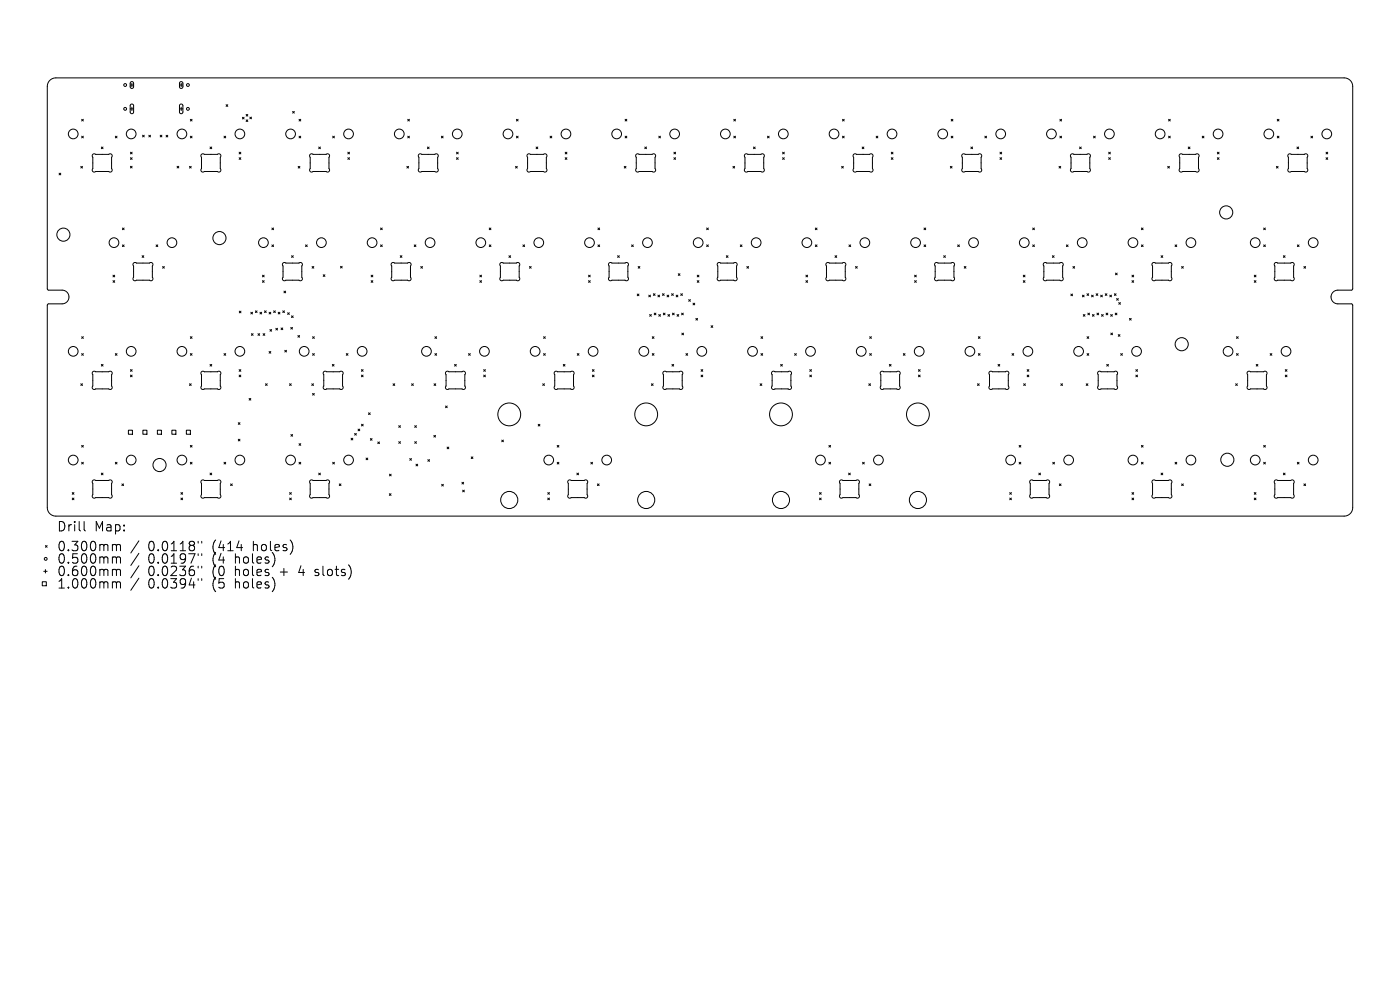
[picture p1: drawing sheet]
<svg xmlns="http://www.w3.org/2000/svg" width="297mm" height="210mm" viewBox="0 0 297 210" stroke-linecap="round" stroke-linejoin="round" font-family="sans-serif">
<defs><g id="words">
<g font-size="2.8">
<text x="12" y="113">Drill</text>
<text x="20" y="113">Map:</text>
<text x="12" y="117.2">0.300mm</text>
<text x="12" y="119.9">0.500mm</text>
<text x="31.4" y="117.2">0.0118&quot;</text>
<text x="31.4" y="119.9">0.0197&quot;</text>
<text x="45.2" y="117.2">(414</text>
<text x="45.2" y="119.9">(4</text>
<text x="50.1" y="119.9">holes)</text>
<text x="53.9" y="117.2">holes)</text>
<text x="12" y="122.5">0.600mm</text>
<text x="12" y="125.1">1.000mm</text>
<text x="31.4" y="122.5">0.0236&quot;</text>
<text x="31.4" y="125.1">0.0394&quot;</text>
<text x="45.2" y="122.5">(0</text>
<text x="45.2" y="125.1">(5</text>
<text x="50.1" y="122.5">holes</text>
<text x="50.1" y="125.1">holes)</text>
<text x="59.9" y="122.5">+</text>
<text x="64.1" y="122.5">4</text>
<text x="67.7" y="122.5">slots)</text>
</g>
</g></defs>
<g fill="none" stroke="#000" stroke-width=".21">
<path d="M10.6 17.1l.6-.5 .6-.1h273.4a1.81 1.81 0 0 1 1.8 1.8v43l-.3 .2h-2.9a1.45 1.45 0 0 0-1.4 1.5 1.45 1.45 0 0 0 1.4 1.5h2.9l.3 .2v43a1.81 1.81 0 0 1-1.8 1.8h-273.4a1.82 1.82 0 0 1-1.8-1.8v-43l.3-.2h2.9a1.45 1.45 0 0 0 1.4-1.5 1.45 1.45 0 0 0-1.4-1.5h-2.9l-.3-.2v-43l.2-.7zM27.6 18h.7M27.7 17.4l.4-.1 .2 .3v.9l-.2 .2h-.3l-.2-.2zM28 17.7v.7M38.1 18h.7M38.2 17.4l.3-.1 .3 .3v.9l-.3 .2h-.2l-.2-.2zM38.4 17.7v.7M12.5 36.7l.4 .4M12.9 36.7l-.4 .4M17.1 35.3l.4 .4M17.3 25.3l.4 .4M17.3 28.9l.4 .4"/>
<path d="M17.5 35.3l-.4 .4M17.7 25.3l-.4 .4M17.7 28.9l-.4 .4M19.7 32.7l.3-.1 .3 .1h2.8l.3-.1 .3 .1 .1 .4-.1 .3v3l-.3 .1-.3-.1h-2.8l-.3 .1-.3-.1-.1-.3 .1-.3v-2.4l-.1-.3zM21.5 31.2l.4 .3M21.9 31.2l-.4 .3M24.5 28.9l.3 .4M24.8 28.9l-.3 .4M27.6 23.1h.7M27.7 35.3l.3 .3M27.7 32.3l.3 .4M27.7 33.5l.3 .3"/>
<path d="M27.7 22.2l.4-.1 .2 .3v1.4l-.3 .3h-.2l-.2-.3zM28 22.7v.8M28 35.3l-.3 .3M28 32.3l-.3 .4M28 33.5l-.3 .3M30.2 28.7l.4 .3M30.6 28.7l-.4 .3M31.6 28.7l.3 .4M31.9 28.7l-.3 .4M34 28.7l.3 .3M34.3 28.7l-.3 .3M35.2 28.7l.4 .4"/>
<path d="M35.6 28.7l-.4 .4M37.6 35.3l.3 .3M37.9 35.3l-.3 .3M38.1 23.1h.7M38.2 22.2l.3-.1 .3 .3v1.4l-.3 .3h-.3l-.1-.3zM38.4 22.7v.8M40.2 35.3l.4 .4M40.4 25.3l.3 .4M40.4 28.9l.3 .4M40.6 35.3l-.4 .4M40.7 25.3l-.3 .4M40.7 28.9l-.3 .4"/>
<path d="M42.7 32.7l.3-.1 .3 .1h2.8l.3-.1 .3 .1 .2 .4-.2 .3 .1 3-.4 .1-.3-.1h-2.8l-.3 .1-.2-.1-.2-.3 .1-.3v-2.4l-.1-.3zM44.6 31.2l.3 .3M44.9 31.2l-.3 .3M47.5 28.9l.4 .4M47.9 28.9l-.4 .4M48 22.2l.3 .4M48.3 22.2l-.3 .4M50.7 32.3l.4 .4M50.7 33.5l.4 .3M51.1 32.3l-.4 .4M51.1 33.5l-.4 .3M51.4 24.9l.4 .3"/>
<path d="M51.8 24.9l-.4 .3M52.2 24.3l.4 .3M52.2 25.4l.4 .4M52.6 24.3l-.4 .3M52.6 25.4l-.4 .4M53 24.8l.4 .4M53.4 24.8l-.4 .4M62.1 23.6l.3 .4M62.4 23.6l-.3 .4M63.3 35.3l.3 .4M63.4 25.3l.4 .4M63.4 28.9l.4 .4"/>
<path d="M63.6 35.3l-.3 .4M63.8 25.3l-.4 .4M63.8 28.9l-.4 .4M65.8 32.7l.3-.1 .3 .1h2.8l.3-.1 .3 .1 .1 .4-.1 .3v3l-.3 .1-.3-.1h-2.8l-.3 .1-.3-.1-.1-.3 .1-.3v-2.4l-.1-.3zM67.6 31.2l.4 .3M68 31.2l-.4 .3M70.6 28.9l.3 .4M70.9 28.9l-.3 .4M73.8 32.3l.4 .4M73.8 33.5l.4 .3M74.2 32.3l-.4 .4M74.2 33.5l-.4 .3"/>
<path d="M86.3 35.3l.4 .4M86.5 25.3l.4 .4M86.5 28.9l.4 .4M86.7 35.3l-.4 .4M86.9 28.9l-.4 .4M86.9 25.3l-.4 .4M88.9 32.7l.3-.1 .3 .1h2.7l.4-.1 .2 .1 .2 .4-.2 .3 .1 3-.4 .1-.3-.1h-2.7l-.3 .1-.3-.1-.2-.3 .2-.3v-2.4l-.2-.3zM90.7 31.2l.3 .3M91 31.2l-.3 .3M93.6 28.9l.4 .4M94 28.9l-.4 .4M96.8 32.3l.4 .4"/>
<path d="M96.8 33.5l.4 .3M97.2 33.5l-.4 .3M97.2 32.3l-.4 .4M109.4 35.3l.3 .4M109.6 25.3l.3 .4M109.6 28.9l.3 .4M109.7 35.3l-.3 .4M109.9 25.3l-.3 .4M109.9 28.9l-.3 .4M111.9 32.7l.3-.1 .3 .1h2.8l.3-.1 .3 .1 .1 .4-.1 .3v3l-.3 .1-.3-.1h-2.8l-.3 .1-.3-.1-.1-.3 .1-.3v-2.4l-.1-.3zM113.7 31.2l.4 .3M114.1 31.2l-.4 .3"/>
<path d="M116.7 28.9l.4 .4M117.1 28.9l-.4 .4M119.9 32.3l.4 .4M119.9 33.5l.4 .3M120.3 32.3l-.4 .4M120.3 33.5l-.4 .3M132.4 35.3l.4 .4M132.6 25.3l.4 .4M132.6 28.9l.4 .4M132.8 35.3l-.4 .4M133 28.9l-.4 .4M133 25.3l-.4 .4"/>
<path d="M135 32.7l.3-.1 .3 .1h2.8l.3-.1 .2 .1 .2 .4-.1 .3v3l-.3 .1-.3-.1h-2.8l-.3 .1-.3-.1-.2-.3 .2-.3v-2.4l-.2-.3zM136.8 31.2l.4 .3M137.2 31.2l-.4 .3M139.8 28.9l.3 .4M140.1 28.9l-.3 .4M143 32.3l.3 .4M143 33.5l.3 .3M143.3 32.3l-.3 .4M143.3 33.5l-.3 .3M155.5 35.3l.4 .4M155.7 25.3l.3 .4M155.7 28.9l.3 .4"/>
<path d="M155.9 35.3l-.4 .4M156 25.3l-.3 .4M156 28.9l-.3 .4M158 32.7l.3-.1 .3 .1h2.8l.3-.1 .3 .1 .2 .4-.2 .3 .1 3-.4 .1-.3-.1h-2.8l-.3 .1-.2-.1-.2-.3 .1-.3v-2.4l-.1-.3zM159.8 31.2l.4 .3M160.2 31.2l-.4 .3M162.8 28.9l.4 .4M163.2 28.9l-.4 .4M166 32.3l.4 .4M166 33.5l.4 .3M166.4 32.3l-.4 .4M166.4 33.5l-.4 .3"/>
<path d="M178.5 35.3l.4 .4M178.7 25.3l.4 .4M178.7 28.9l.4 .4M178.9 35.3l-.4 .4M179.1 25.3l-.4 .4M179.1 28.9l-.4 .4M181.1 32.7l.3-.1 .3 .1h2.8l.3-.1 .3 .1 .1 .4-.1 .3v3l-.3 .1-.3-.1h-2.8l-.3 .1-.3-.1-.1-.3 .1-.3v-2.4l-.1-.3zM182.9 31.2l.4 .3M183.3 31.2l-.4 .3M185.9 28.9l.3 .4M186.2 28.9l-.3 .4M189.1 32.3l.3 .4"/>
<path d="M189.1 33.5l.3 .3M189.4 32.3l-.3 .4M189.4 33.5l-.3 .3M201.6 35.3l.4 .4M201.8 25.3l.4 .4M201.8 28.9l.4 .4M202 35.3l-.4 .4M202.2 25.3l-.4 .4M202.2 28.9l-.4 .4M204.1 32.7l.4-.1 .3 .1h2.7l.3-.1 .3 .1 .2 .4-.2 .3 .1 3-.4 .1-.3-.1h-2.7l-.4 .1-.2-.1-.2-.3 .2-.3v-2.4l-.2-.3zM206 31.2l.3 .3M206.3 31.2l-.3 .3"/>
<path d="M208.9 28.9l.4 .4M209.3 28.9l-.4 .4M212.1 32.3l.4 .4M212.1 33.5l.4 .3M212.5 32.3l-.4 .4M212.5 33.5l-.4 .3M224.7 35.3l.3 .4M224.8 25.3l.4 .4M224.8 28.9l.4 .4M225 35.3l-.3 .4M225.2 25.3l-.4 .4M225.2 28.9l-.4 .4"/>
<path d="M227.2 32.7l.3-.1 .3 .1h2.8l.3-.1 .3 .1 .1 .4-.1 .3v3l-.3 .1-.3-.1h-2.8l-.3 .1-.3-.1-.1-.3 .1-.3v-2.4l-.1-.3zM229 31.2l.4 .3M229.4 31.2l-.4 .3M232 28.9l.4 .4M232.4 28.9l-.4 .4M235.2 32.3l.4 .4M235.2 33.5l.4 .3M235.6 32.3l-.4 .4M235.6 33.5l-.4 .3M247.7 35.3l.4 .4M247.9 25.3l.4 .4M247.9 28.9l.4 .4"/>
<path d="M248.1 35.3l-.4 .4M248.3 25.3l-.4 .4M248.3 28.9l-.4 .4M250.3 32.7l.3-.1 .3 .1h2.8l.3-.1 .2 .1 .2 .3-.1 .4v3l-.3 .1-.3-.1h-2.8l-.3 .1-.3-.1-.2-.3 .2-.3v-2.4l-.2-.3zM252.1 31.2l.3 .3M252.4 31.2l-.3 .3M255 28.9l.4 .4M255.4 28.9l-.4 .4M258.3 32.3l.3 .4M258.3 33.5l.3 .3M258.6 32.3l-.3 .4M258.6 33.5l-.3 .3"/>
<path d="M270.8 35.3l.3 .4M271 25.3l.3 .4M271 28.9l.3 .4M271.1 35.3l-.3 .4M271.3 25.3l-.3 .4M271.3 28.9l-.3 .4M273.3 32.7l.3-.1 .3 .1h2.8l.3-.1 .3 .1 .1 .3-.1 .4v3l-.3 .1-.3-.1h-2.8l-.3 .1-.3-.1-.1-.3 .1-.3v-2.4l-.1-.3zM275.1 31.2l.4 .3M275.5 31.2l-.4 .3M278.1 28.9l.4 .4M278.5 28.9l-.4 .4M281.3 32.3l.4 .4"/>
<path d="M281.3 33.5l.4 .3M281.7 32.3l-.4 .4M281.7 33.5l-.4 .3M24 58.4l.3 .3M24 59.5l.3 .4M24.3 58.4l-.3 .3M24.3 59.5l-.3 .4M26 48.4l.3 .3M26 51.9l.3 .4M26.3 48.4l-.3 .3M26.3 51.9l-.3 .4M28.3 55.8l.3-.1 .3 .1h2.8l.3-.1 .3 .1 .1 .3-.1 .3v3l-.3 .2-.3-.2h-2.8l-.3 .2-.2-.1-.2-.4 .1-.3v-2.4l-.1-.3z"/>
<path d="M30.1 54.2l.4 .4M30.5 54.2l-.4 .4M33.1 51.9l.4 .4M33.5 51.9l-.4 .4M34.5 56.5l.4 .4M34.9 56.5l-.4 .4M55.7 58.4l.3 .3M55.7 59.5l.3 .4M56 58.4l-.3 .3M56 59.5l-.3 .4M57.7 48.4l.3 .3M57.7 51.9l.3 .4"/>
<path d="M58 48.4l-.3 .3M58 51.9l-.3 .4M60 55.8l.3-.1 .3 .1h2.8l.3-.1 .3 .1 .2 .3-.2 .3 .1 3-.4 .2-.3-.2h-2.8l-.3 .2-.2-.1-.2-.4 .1-.3v-2.4l-.1-.3zM61.9 54.2l.3 .4M62.2 54.2l-.3 .4M64.8 51.9l.4 .4M65.2 51.9l-.4 .4M66.2 56.5l.4 .4M66.6 56.5l-.4 .4M68.6 58.3l.3 .3M68.9 58.3l-.3 .3M72.2 56.5l.4 .4"/>
<path d="M72.6 56.5l-.4 .4M78.7 58.4l.4 .3M78.7 59.5l.4 .4M79.1 58.4l-.4 .3M79.1 59.5l-.4 .4M80.7 48.4l.4 .3M80.7 51.9l.4 .4M81.1 48.4l-.4 .3M81.1 51.9l-.4 .4M83.1 55.8l.3-.1 .3 .1h2.8l.3-.1 .3 .1 .1 .3-.1 .3v3l-.3 .2-.3-.2h-2.8l-.3 .2-.3-.1-.1-.4 .1-.3v-2.4l-.1-.3zM84.9 54.2l.4 .4M85.3 54.2l-.4 .4"/>
<path d="M87.9 51.9l.3 .4M88.2 51.9l-.3 .4M89.3 56.5l.3 .4M89.6 56.5l-.3 .4M101.8 58.4l.4 .3M101.8 59.5l.4 .4M102.2 58.4l-.4 .3M102.2 59.5l-.4 .4M103.8 48.4l.4 .3M103.8 51.9l.4 .4M104.2 48.4l-.4 .3M104.2 51.9l-.4 .4"/>
<path d="M106.2 55.8l.3-.1 .3 .1h2.7l.4-.1 .2 .1 .2 .3-.2 .3 .1 3-.4 .2-.3-.2h-2.7l-.4 .2-.2-.1-.2-.4 .2-.3v-2.4l-.2-.3zM108 54.2l.3 .4M108.3 54.2l-.3 .4M110.9 51.9l.4 .4M111.3 51.9l-.4 .4M112.3 56.5l.4 .4M112.7 56.5l-.4 .4M124.9 58.4l.3 .3M124.9 59.5l.3 .4M125.2 59.5l-.3 .4M125.2 58.4l-.3 .3M126.8 48.4l.4 .3"/>
<path d="M126.8 51.9l.4 .4M127.2 48.4l-.4 .3M127.2 51.9l-.4 .4M129.2 55.8l.3-.1 .3 .1h2.8l.3-.1 .3 .1 .1 .3-.1 .3v3l-.3 .2-.3-.2h-2.8l-.3 .2-.3-.1-.1-.4 .1-.3v-2.4l-.1-.3zM131 54.2l.4 .4M131.4 54.2l-.4 .4M134 51.9l.4 .4M134.4 51.9l-.4 .4M135.4 56.5l.3 .4M135.7 56.5l-.3 .4M143.9 58.1l.4 .3M144.3 58.1l-.4 .3"/>
<path d="M147.9 58.4l.4 .3M147.9 59.5l.4 .4M148.3 58.4l-.4 .3M148.3 59.5l-.4 .4M149.9 48.4l.4 .3M149.9 51.9l.4 .4M150.3 48.4l-.4 .3M150.3 51.9l-.4 .4M152.3 55.8l.3-.1 .3 .1h2.8l.3-.1 .2 .1 .2 .3-.1 .3v3l-.3 .2-.3-.2h-2.8l-.3 .2-.3-.1-.2-.4 .2-.3v-2.4l-.2-.3zM154.1 54.2l.3 .4M154.4 54.2l-.3 .4M157 51.9l.4 .4"/>
<path d="M157.4 51.9l-.4 .4M158.4 56.5l.4 .4M158.8 56.5l-.4 .4M171 58.4l.3 .3M171 59.5l.3 .4M171.3 58.4l-.3 .3M171.3 59.5l-.3 .4M173 48.4l.3 .3M173 51.9l.3 .4M173.3 48.4l-.3 .3M173.3 51.9l-.3 .4M175.3 55.8l.3-.1 .3 .1h2.8l.3-.1 .3 .1 .1 .3-.1 .3v3l-.3 .2-.3-.2h-2.8l-.3 .2-.3-.1-.1-.4 .1-.3v-2.4l-.1-.3z"/>
<path d="M177.1 54.2l.4 .4M177.5 54.2l-.4 .4M180.1 51.9l.4 .4M180.5 51.9l-.4 .4M181.5 56.5l.4 .4M181.9 56.5l-.4 .4M194 58.4l.4 .3M194 59.5l.4 .4M194.4 58.4l-.4 .3M194.4 59.5l-.4 .4M196 48.4l.4 .3M196 51.9l.4 .4"/>
<path d="M196.4 48.4l-.4 .3M196.4 51.9l-.4 .4M198.4 55.8l.3-.1 .3 .1h2.8l.3-.1 .3 .1 .1 .3-.1 .3v3l-.3 .2-.3-.2h-2.8l-.3 .2-.3-.1-.1-.4 .1-.3v-2.4l-.1-.3zM200.2 54.2l.4 .4M200.6 54.2l-.4 .4M203.2 51.9l.3 .4M203.5 51.9l-.3 .4M204.6 56.5l.3 .4M204.9 56.5l-.3 .4M217.1 58.4l.3 .3M217.1 59.5l.3 .4M217.4 58.4l-.3 .3"/>
<path d="M217.4 59.5l-.3 .4M219.1 48.4l.3 .3M219.1 51.9l.3 .4M219.4 48.4l-.3 .3M219.4 51.9l-.3 .4M221.4 55.8l.3-.1 .3 .1h2.8l.3-.1 .3 .1 .2 .3-.2 .3 .1 3-.4 .2-.3-.2h-2.8l-.3 .2-.2-.1-.2-.4 .1-.3v-2.4l-.1-.3zM223.3 54.2l.3 .4M223.6 54.2l-.3 .4M226.2 51.9l.4 .4M226.6 51.9l-.4 .4M227.6 56.5l.4 .4M228 56.5l-.4 .4"/>
<path d="M236.6 57.9l.4 .4M237 57.9l-.4 .4M240.1 58.4l.4 .3M240.1 59.5l.4 .4M240.5 58.4l-.4 .3M240.5 59.5l-.4 .4M242.1 48.4l.4 .3M242.1 51.9l.4 .4M242.5 48.4l-.4 .3M242.5 51.9l-.4 .4M244.5 55.8l.3-.1 .3 .1h2.8l.3-.1 .3 .1 .1 .3-.1 .3v3l-.3 .2-.3-.2h-2.8l-.3 .2-.3-.1-.1-.4 .1-.3v-2.4l-.1-.3zM246.3 54.2l.4 .4"/>
<path d="M246.7 54.2l-.4 .4M249.3 51.9l.3 .4M249.6 51.9l-.3 .4M250.7 56.5l.3 .4M251 56.5l-.3 .4M266.1 58.4l.3 .3M266.1 59.5l.3 .4M266.4 58.4l-.3 .3M266.4 59.5l-.3 .4M268.1 48.4l.3 .3M268.1 51.9l.3 .4M268.4 48.4l-.3 .3"/>
<path d="M268.4 51.9l-.3 .4M270.4 55.8l.3-.1 .3 .1h2.8l.3-.1 .3 .1 .2 .3-.2 .3 .1 3-.4 .2-.3-.2h-2.8l-.3 .2-.2-.1-.2-.3 .1-.4v-2.4l-.1-.3zM272.3 54.2l.3 .4M272.6 54.2l-.3 .4M275.2 51.9l.4 .4M275.6 51.9l-.4 .4M276.6 56.5l.4 .4M277 56.5l-.4 .4M17.3 71.4l.4 .4M17.3 75l.4 .4M17.7 71.4l-.4 .4M17.7 75l-.4 .4"/>
<path d="M19.7 78.9l.3-.2 .3 .2h2.8l.3-.2 .3 .1 .1 .4-.1 .3v3l-.3 .1-.3-.1h-2.8l-.3 .1-.3-.1-.1-.3 .1-.3v-2.4l-.1-.3zM21.5 77.3l.4 .4M21.9 77.3l-.4 .4M24.5 75l.3 .4M24.8 75l-.3 .4M27.7 78.4l.3 .4M27.7 79.6l.3 .3M28 78.4l-.3 .4M28 79.6l-.3 .3M40.4 71.4l.3 .4M40.4 75l.3 .4M40.7 71.4l-.3 .4"/>
<path d="M40.7 75l-.3 .4M42.7 78.9l.3-.2 .3 .2h2.8l.3-.2 .3 .1 .2 .4-.2 .3 .1 3-.4 .1-.3-.1h-2.8l-.3 .1-.2-.1-.2-.3 .1-.3v-2.4l-.1-.3zM44.6 77.3l.3 .4M44.9 77.3l-.3 .4M47.5 75l.4 .4M47.9 75l-.4 .4M50.7 78.4l.4 .4M50.7 79.6l.4 .3M50.8 66l.3 .4M51.1 78.4l-.4 .4M51.1 79.6l-.4 .3M51.1 66l-.3 .4"/>
<path d="M53.2 66.2l.4 .4M53.3 70.8l.4 .3M53.6 66.2l-.4 .4M53.7 70.8l-.4 .3M54.2 65.9l.3 .4M54.5 65.9l-.3 .4M54.7 70.8l.4 .3M55.1 70.8l-.4 .3M55.1 66.2l.4 .4M55.5 66.2l-.4 .4M55.8 70.8l.4 .3M56.1 65.9l.4 .4"/>
<path d="M56.2 70.8l-.4 .3M56.5 65.9l-.4 .4M57.1 74.6l.3 .3M57.1 66.2l.3 .4M57.3 69.9l.3 .4M57.4 66.2l-.3 .4M57.4 74.6l-.3 .3M57.6 69.9l-.3 .4M58.1 65.9l.3 .4M58.4 65.9l-.3 .4M58.5 69.6l.4 .4M58.9 69.6l-.4 .4"/>
<path d="M59 66.2l.4 .4M59.4 66.2l-.4 .4M59.6 69.6l.4 .3M60 69.6l-.4 .3M60 65.9l.4 .4M60.2 61.8l.4 .3M60.4 65.9l-.4 .4M60.4 74.3l.4 .4M60.6 61.8l-.4 .3M60.8 74.3l-.4 .4M61 66.3l.4 .4M61.4 66.3l-.4 .4"/>
<path d="M61.7 69.5l.4 .3M61.8 67l.4 .4M62.1 69.5l-.4 .3M62.2 67l-.4 .4M63.2 71.2l.4 .3M63.6 71.2l-.4 .3M66.3 71.4l.4 .4M66.3 75l.4 .4M66.7 71.4l-.4 .4M66.7 75l-.4 .4M68.7 78.9l.3-.2 .3 .2h2.8l.3-.2 .3 .1 .1 .4-.1 .3v3l-.3 .1-.3-.1h-2.8l-.3 .1-.3-.1-.1-.3 .1-.3v-2.4l-.1-.3zM70.5 77.3l.4 .4"/>
<path d="M70.9 77.3l-.4 .4M73.5 75l.3 .4M73.8 75l-.3 .4M76.7 78.4l.3 .4M76.7 79.6l.3 .3M77 78.4l-.3 .4M77 79.6l-.3 .3M92.3 71.4l.3 .4M92.3 75l.3 .4M92.6 71.4l-.3 .4M92.6 75l-.3 .4M94.6 78.9l.3-.2 .3 .2h2.8l.3-.2 .3 .1 .1 .4-.1 .3v3l-.3 .1-.3-.1h-2.8l-.3 .1-.3-.1-.1-.3 .1-.3v-2.4l-.1-.3z"/>
<path d="M96.4 77.3l.4 .4M96.8 77.3l-.4 .4M99.4 75l.4 .4M99.8 75l-.4 .4M102.6 78.4l.4 .4M102.6 79.6l.4 .3M103 78.4l-.4 .4M103 79.6l-.4 .3M115.3 71.4l.4 .4M115.3 75l.4 .4M115.7 71.4l-.4 .4M115.7 75l-.4 .4"/>
<path d="M117.7 78.9l.3-.2 .3 .2h2.8l.3-.2 .3 .1 .1 .4-.1 .3v3l-.3 .1-.3-.1h-2.8l-.3 .1-.3-.1-.1-.3 .1-.3v-2.4l-.1-.3zM119.5 77.3l.4 .4M119.9 77.3l-.4 .4M122.5 75l.3 .4M122.8 75l-.3 .4M125.7 78.4l.3 .4M125.7 79.6l.3 .3M126 78.4l-.3 .4M126 79.6l-.3 .3M135.2 62.4l.3 .3M135.5 62.4l-.3 .3M137.6 62.6l.4 .4"/>
<path d="M137.8 66.7l.4 .4M138 62.6l-.4 .4M138.2 66.7l-.4 .4M138.4 71.4l.3 .4M138.4 75l.3 .4M138.6 62.3l.4 .4M138.7 71.4l-.3 .4M138.7 75l-.3 .4M138.8 66.4l.4 .4M139 62.3l-.4 .4M139.2 66.4l-.4 .4M139.6 62.6l.3 .4"/>
<path d="M139.8 66.7l.3 .4M139.9 62.6l-.3 .4M140.1 66.7l-.3 .4M140.5 62.3l.4 .4M140.7 66.4l.4 .4M140.7 78.9l.3-.2 .3 .2h2.8l.3-.2 .3 .1 .2 .4-.2 .3 .1 3-.4 .1-.3-.1h-2.8l-.3 .1-.2-.1-.2-.3 .1-.3v-2.4l-.1-.3zM140.9 62.3l-.4 .4M141.1 66.4l-.4 .4M141.5 62.6l.4 .4M141.7 66.7l.4 .4M141.9 62.6l-.4 .4M142.1 66.7l-.4 .4"/>
<path d="M142.5 62.3l.3 .4M142.6 77.3l.3 .4M142.7 66.4l.3 .4M142.8 62.3l-.3 .4M142.9 77.3l-.3 .4M143 66.4l-.3 .4M143.4 62.6l.4 .4M143.6 66.7l.4 .4M143.8 62.6l-.4 .4M144 66.7l-.4 .4M144.4 62.3l.4 .4M144.6 66.4l.4 .4"/>
<path d="M144.7 70.7l.3 .3M144.8 62.3l-.4 .4M145 66.4l-.4 .4M145 70.7l-.3 .3M145.5 75l.4 .4M145.9 75l-.4 .4M146.1 63.6l.4 .3M146.5 63.6l-.4 .3M147 64.3l.4 .4M147.4 64.3l-.4 .4M147.6 67.5l.4 .4M148 67.5l-.4 .4"/>
<path d="M148.7 78.4l.4 .4M148.7 79.6l.4 .3M149.1 78.4l-.4 .4M149.1 79.6l-.4 .3M150.8 69.1l.4 .4M151.2 69.1l-.4 .4M161.4 71.4l.4 .4M161.4 75l.4 .4M161.8 71.4l-.4 .4M161.8 75l-.4 .4M163.8 78.9l.3-.2 .3 .2h2.8l.3-.2 .3 .1 .1 .4-.1 .3v3l-.3 .1-.3-.1h-2.8l-.3 .1-.3-.1-.1-.3 .1-.3v-2.4l-.1-.3zM165.6 77.3l.4 .4"/>
<path d="M166 77.3l-.4 .4M168.6 75l.3 .4M168.9 75l-.3 .4M171.8 78.4l.3 .4M171.8 79.6l.3 .3M172.1 78.4l-.3 .4M172.1 79.6l-.3 .3M184.5 71.4l.4 .4M184.5 75l.4 .4M184.9 71.4l-.4 .4M184.9 75l-.4 .4M186.9 78.9l.3-.2 .3 .2h2.7l.4-.2 .2 .1 .2 .4-.2 .3 .1 3-.4 .1-.3-.1h-2.7l-.3 .1-.3-.1-.2-.3 .2-.3v-2.4l-.2-.3z"/>
<path d="M188.7 77.3l.3 .4M189 77.3l-.3 .4M191.6 75l.4 .4M192 75l-.4 .4M194.8 78.4l.4 .4M194.8 79.6l.4 .3M195.2 78.4l-.4 .4M195.2 79.6l-.4 .3M207.6 71.4l.3 .4M207.6 75l.3 .4M207.9 71.4l-.3 .4M207.9 75l-.3 .4"/>
<path d="M209.9 78.9l.3-.2 .3 .2h2.8l.3-.2 .3 .1 .1 .4-.1 .3v3l-.3 .1-.3-.1h-2.8l-.3 .1-.3-.1-.1-.3 .1-.3v-2.4l-.1-.3zM211.7 77.3l.4 .4M212.1 77.3l-.4 .4M214.7 75l.4 .4M215.1 75l-.4 .4M217.9 78.4l.4 .4M217.9 79.6l.4 .3M218.3 78.4l-.4 .4M218.3 79.6l-.4 .3M227.2 62.4l.3 .3M227.5 62.4l-.3 .3M229.6 62.6l.4 .4"/>
<path d="M229.8 66.7l.4 .4M230 62.6l-.4 .4M230.2 66.7l-.4 .4M230.6 62.3l.4 .4M230.6 71.4l.4 .4M230.6 75l.4 .4M230.8 66.4l.3 .4M231 62.3l-.4 .4M231 71.4l-.4 .4M231 75l-.4 .4M231.1 66.4l-.3 .4M231.6 62.6l.3 .4"/>
<path d="M231.7 66.7l.4 .4M231.9 62.6l-.3 .4M232.1 66.7l-.4 .4M232.5 62.3l.4 .4M232.7 66.4l.4 .4M232.9 62.3l-.4 .4M233 78.9l.3-.2 .3 .2h2.8l.3-.2 .2 .1 .2 .4-.1 .3v3l-.3 .1-.3-.1h-2.8l-.3 .1-.3-.1-.2-.3 .2-.3v-2.4l-.2-.3zM233.1 66.4l-.4 .4M233.5 62.6l.4 .4M233.7 66.7l.3 .4M233.9 62.6l-.4 .4M234 66.7l-.3 .4"/>
<path d="M234.5 62.3l.3 .4M234.7 66.4l.3 .4M234.8 77.3l.4 .4M234.8 62.3l-.3 .4M235 66.4l-.3 .4M235.2 77.3l-.4 .4M235.4 62.6l.4 .4M235.6 66.7l.4 .4M235.7 70.7l.3 .3M235.8 62.6l-.4 .4M236 66.7l-.4 .4M236 70.7l-.3 .3"/>
<path d="M236.4 62.3l.4 .4M236.6 66.4l.4 .4M236.8 62.3l-.4 .4M236.9 63.3l.3 .4M237 66.4l-.4 .4M237.2 71l.4 .3M237.2 63.3l-.3 .4M237.3 64.2l.4 .3M237.6 71l-.4 .3M237.7 64.2l-.4 .3M237.8 75l.3 .4M238.1 75l-.3 .4"/>
<path d="M239.6 67.5l.4 .4M240 67.5l-.4 .4M241 78.4l.3 .4M241 79.6l.3 .3M241.3 78.4l-.3 .4M241.3 79.6l-.3 .3M262.3 71.4l.4 .4M262.3 75l.4 .4M262.7 71.4l-.4 .4M262.7 75l-.4 .4M264.7 78.9l.3-.2 .3 .2h2.8l.3-.2 .3 .1 .1 .4-.1 .3v3l-.3 .1-.3-.1h-2.8l-.3 .1-.3-.1-.1-.3 .1-.3v-2.4l-.1-.3zM266.5 77.3l.4 .4"/>
<path d="M266.9 77.3l-.4 .4M269.5 75l.3 .4M269.8 75l-.3 .4M272.7 78.4l.3 .4M272.7 79.6l.3 .3M273 78.4l-.3 .4M273 79.6l-.3 .3M17.1 81.4l.4 .4M17.3 94.5l.4 .3M17.3 98.1l.4 .3M17.5 81.4l-.4 .4M17.7 94.5l-.4 .3"/>
<path d="M17.7 98.1l-.4 .3M24.5 98.1l.3 .3M24.8 98.1l-.3 .3M27.2 91.3h.9v.8h-.9zM30.3 91.3h.9v.8h-.9zM33.4 91.3h.8v.8h-.8zM36.5 91.3h.8v.8h-.8zM39.5 91.3h.9v.8h-.9zM40.2 81.4l.4 .4M40.4 94.5l.3 .3M40.4 98.1l.3 .3M40.6 81.4l-.4 .4"/>
<path d="M40.7 94.5l-.3 .3M40.7 98.1l-.3 .3M47.5 98.1l.4 .3M47.9 98.1l-.4 .3M50.5 89.7l.4 .3M50.5 93.2l.4 .3M50.9 89.7l-.4 .3M50.9 93.2l-.4 .3M52.8 84.5l.4 .4M53.2 84.5l-.4 .4M56.3 81.4l.4 .4M56.7 81.4l-.4 .4"/>
<path d="M61.4 81.4l.4 .4M61.7 92.2l.4 .3M61.8 81.4l-.4 .4M62.1 92.2l-.4 .3M63.4 94.1l.4 .4M63.4 98.1l.4 .3M63.8 94.1l-.4 .4M63.8 98.1l-.4 .3M66.1 81.4l.4 .4M66.3 83.5l.4 .3M66.5 81.4l-.4 .4M66.7 83.5l-.4 .3"/>
<path d="M70.6 98.1l.3 .3M70.9 98.1l-.3 .3M74.5 93l.3 .3M74.8 93l-.3 .3M75.2 91.9l.4 .4M75.6 91.9l-.4 .4M76 91l.3 .4M76.3 91l-.3 .4M76.7 90l.4 .4M77.1 90l-.4 .4M77.7 97.2l.3 .3M78 97.2l-.3 .3"/>
<path d="M78.2 87.6l.3 .3M78.5 87.6l-.3 .3M78.6 93l.3 .4M78.9 93l-.3 .4M80.1 93.7l.4 .4M80.5 93.7l-.4 .4M83.4 81.4l.3 .4M83.7 81.4l-.3 .4M84.6 90.3l.4 .4M84.6 93.7l.4 .3M85 90.3l-.4 .4M85 93.7l-.4 .3"/>
<path d="M86.9 97.3l.4 .3M87.3 97.3l-.4 .3M87.3 81.4l.4 .4M87.7 81.4l-.4 .4M88 93.7l.3 .3M88 90.3l.3 .4M88.3 98.5l.3 .3M88.3 90.3l-.3 .4M88.3 93.7l-.3 .3M88.6 98.5l-.3 .3M90.8 97.5l.3 .4M91.1 97.5l-.3 .4"/>
<path d="M92 92.4l.4 .3M92.1 81.4l.3 .4M92.4 92.4l-.4 .3M92.4 81.4l-.3 .4M94.5 86.1l.4 .4M94.8 94.8l.4 .4M94.9 86.1l-.4 .4M95.2 94.8l-.4 .4M100 96.9l.3 .4M100.3 96.9l-.3 .4M106.4 93.4l.4 .3M106.8 93.4l-.4 .3"/>
<path d="M114.2 90l.3 .4M114.5 90l-.3 .4M115.1 81.4l.4 .4M115.5 81.4l-.4 .4M118.2 94.5l.4 .3M118.2 98.1l.4 .3M118.6 94.5l-.4 .3M118.6 98.1l-.4 .3M125.3 98.1l.4 .3M125.7 98.1l-.4 .3M138.2 81.4l.4 .4M138.6 81.4l-.4 .4"/>
<path d="M161.3 81.4l.3 .4M161.6 81.4l-.3 .4M175.8 94.5l.4 .3M175.8 98.1l.4 .3M176.2 94.5l-.4 .3M176.2 98.1l-.4 .3M183 98.1l.4 .3M183.4 98.1l-.4 .3M184.3 81.4l.4 .4M184.7 81.4l-.4 .4M207.4 81.4l.3 .4M207.7 81.4l-.3 .4"/>
<path d="M216.2 94.5l.4 .3M216.2 98.1l.4 .3M216.6 94.5l-.4 .3M216.6 98.1l-.4 .3M217.2 81.4l.3 .4M217.5 81.4l-.3 .4M223.3 98.1l.4 .3M223.7 98.1l-.4 .3M225 81.4l.4 .4M225.4 81.4l-.4 .4M230.4 81.4l.4 .4M230.8 81.4l-.4 .4"/>
<path d="M242.1 94.5l.4 .3M242.1 98.1l.4 .3M242.5 94.5l-.4 .3M242.5 98.1l-.4 .3M249.3 98.1l.3 .3M249.6 98.1l-.3 .3M262.1 81.4l.4 .4M262.5 81.4l-.4 .4M268.1 94.5l.3 .3M268.1 98.1l.3 .3M268.4 94.5l-.3 .3M268.4 98.1l-.3 .3"/>
<path d="M275.2 98.1l.4 .3M275.6 98.1l-.4 .3M9.6 115.7l.4 .4M10 115.7l-.4 .4M15.3 104.5l.4 .4M15.3 105.7l.4 .3M15.7 104.5l-.4 .4M15.7 105.7l-.4 .3M17.8 110.6v1.7l.3 .3M19.7 101.9l.3-.1 .3 .1h2.8l.3-.1 .3 .1 .1 .3-.1 .3v3l-.3 .2-.3-.1h-2.8l-.3 .1-.3-.1-.1-.4 .1-.3v-2.4l-.1-.3zM21.5 100.4l.4 .3M21.9 100.4l-.4 .3"/>
<path d="M24.1 115.5l.5 .1 .1 .2M24.1 118.1l.5 .1 .1 .2M24.7 115.8l.3-.3 .5 .1 .1 1.2M24.7 115.8v1M24.7 118.4v1.1M24.7 118.4l.3-.3 .5 .1 .1 1.3M25.9 102.6l.3 .4M26.2 102.6l-.3 .4M29.5 114.7l-1.7 2.6M29.5 117.4l-1.7 2.5M38.4 104.5l.3 .4M38.4 105.7l.3 .3"/>
<path d="M38.7 104.5l-.3 .4M38.7 105.7l-.3 .3M42 114.8v.4M42 117.5v.3M42.7 101.9l.3-.1 .3 .1h2.8l.3-.1 .3 .1 .2 .3-.2 .3 .1 3-.4 .2-.3-.1h-2.8l-.3 .1-.2-.1-.2-.4 .1-.3v-2.4l-.1-.3zM42.8 114.8v.4M42.8 117.5v.3M44.6 100.4l.3 .3M44.9 100.4l-.3 .3M48.9 102.6l.4 .4M49.3 102.6l-.4 .4M61.4 104.5l.4 .4"/>
<path d="M61.4 105.7l.4 .3M61.8 104.5l-.4 .4M61.8 105.7l-.4 .3M65.8 101.9l.3-.1 .3 .1h2.8l.3-.1 .3 .1 .1 .3-.1 .3v3l-.3 .2-.3-.1h-2.8l-.3 .1-.3-.1-.1-.4 .1-.3v-2.4l-.1-.3zM67.6 100.4l.4 .3M68 100.4l-.4 .3M72 102.6l.3 .4M72.3 102.6l-.3 .4M82.6 104.7l.4 .4M82.6 100.6l.4 .3M83 104.7l-.4 .4M83 100.6l-.4 .3"/>
<path d="M93.7 102.7l.4 .4M94.1 102.7l-.4 .4M98 102.3l.4 .4M98.1 104l.4 .3M98.4 102.3l-.4 .4M98.5 104l-.4 .3M116.2 104.5l.4 .4M116.2 105.7l.4 .3M116.6 104.5l-.4 .4M116.6 105.7l-.4 .3M120.6 101.9l.3-.1 .3 .1h2.8l.3-.1 .2 .1 .2 .3-.1 .3v3l-.3 .2-.3-.1h-2.8l-.3 .1-.3-.1-.2-.4 .2-.3v-2.4l-.2-.3zM122.4 100.4l.3 .3"/>
<path d="M122.7 100.4l-.3 .3M126.7 102.6l.4 .4M127.1 102.6l-.4 .4M173.9 104.5l.3 .4M173.9 105.7l.3 .3M174.2 104.5l-.3 .4M174.2 105.7l-.3 .3M178.2 101.9l.3-.1 .3 .1h2.8l.3-.1 .3 .1 .1 .3-.1 .3v3l-.3 .2-.3-.1h-2.8l-.3 .1-.3-.1-.1-.4 .1-.3v-2.4l-.1-.3zM180 100.4l.4 .3M180.4 100.4l-.4 .3M184.4 102.6l.3 .4M184.7 102.6l-.3 .4"/>
<path d="M214.2 104.5l.4 .4M214.2 105.7l.4 .3M214.6 104.5l-.4 .4M214.6 105.7l-.4 .3M218.6 101.9l.3-.1 .3 .1h2.8l.3-.1 .2 .1 .2 .3-.2 .3 .1 3-.3 .2-.3-.1h-2.8l-.3 .1-.3-.1-.2-.4 .2-.3v-2.4l-.2-.3zM220.4 100.4l.3 .3M220.7 100.4l-.3 .3M224.7 102.6l.4 .4M225.1 102.6l-.4 .4M240.1 105.7l.4 .3M240.1 104.5l.4 .4M240.5 104.5l-.4 .4"/>
<path d="M240.5 105.7l-.4 .3M244.5 101.9l.3-.1 .3 .1h2.8l.3-.1 .3 .1 .1 .3-.1 .3v3l-.3 .2-.3-.1h-2.8l-.3 .1-.3-.1-.1-.4 .1-.3v-2.4l-.1-.3zM246.3 100.4l.4 .3M246.7 100.4l-.4 .3M250.7 102.6l.3 .4M251 102.6l-.3 .4M266.1 104.5l.3 .4M266.1 105.7l.3 .3M266.4 104.5l-.3 .4M266.4 105.7l-.3 .3M270.4 101.9l.3-.1 .3 .1h2.8l.3-.1 .3 .1 .2 .3-.2 .3 .1 3-.4 .2-.3-.1h-2.8l-.3 .1-.2-.1-.2-.3 .1-.4v-2.4l-.1-.3zM272.3 100.4l.3 .3"/>
<path d="M272.6 100.4l-.3 .3M276.6 102.6l.4 .4M277 102.6l-.4 .4M9 123.4h.8v.9h-.8zM9.3 121.2h.7M9.6 120.8v.8M24.1 120.8l.5 .1 .1 .2M24.1 123.4l.5 .1 .1 .2M24.7 121.1v1M24.7 123.7v1M24.7 121.1l.3-.3 .5 .1 .1 1.2M24.7 123.7l.3-.3 .5 .1 .1 1.2"/>
<path d="M29.5 120l-1.7 2.6M29.5 122.7l-1.7 2.5M42 120.1v.4M42 122.7v.4M42.8 120.1v.4M42.8 122.7v.4M66.8 122l.2 .1M66.9 120.9v.4"/>
<circle cx="26.6" cy="18" r=".3"/>
<circle cx="39.9" cy="18" r=".3"/>
<circle cx="15.5" cy="28.4" r="1.03"/>
<circle cx="26.6" cy="23.1" r=".3"/>
<circle cx="27.8" cy="28.4" r="1.03"/>
<circle cx="38.6" cy="28.4" r="1.03"/>
<circle cx="39.9" cy="23.1" r=".3"/>
<circle cx="50.9" cy="28.4" r="1.03"/>
<circle cx="61.6" cy="28.4" r="1.03"/>
<circle cx="73.9" cy="28.4" r="1.03"/>
<circle cx="84.7" cy="28.4" r="1.03"/>
<circle cx="97" cy="28.4" r="1.03"/>
<circle cx="107.8" cy="28.4" r="1.03"/>
<circle cx="120.1" cy="28.4" r="1.03"/>
<circle cx="130.8" cy="28.4" r="1.03"/>
<circle cx="143.1" cy="28.4" r="1.03"/>
<circle cx="153.9" cy="28.4" r="1.03"/>
<circle cx="166.2" cy="28.4" r="1.03"/>
<circle cx="176.9" cy="28.4" r="1.03"/>
<circle cx="189.2" cy="28.4" r="1.03"/>
<circle cx="200" cy="28.4" r="1.03"/>
<circle cx="212.3" cy="28.4" r="1.03"/>
<circle cx="223.1" cy="28.4" r="1.03"/>
<circle cx="235.4" cy="28.4" r="1.03"/>
<circle cx="246.1" cy="28.4" r="1.03"/>
<circle cx="258.4" cy="28.4" r="1.03"/>
<circle cx="269.2" cy="28.4" r="1.03"/>
<circle cx="281.5" cy="28.4" r="1.03"/>
<circle cx="13.4" cy="49.8" r="1.39"/>
<circle cx="24.2" cy="51.5" r="1.03"/>
<circle cx="36.5" cy="51.5" r="1.03"/>
<circle cx="46.6" cy="50.5" r="1.39"/>
<circle cx="55.9" cy="51.5" r="1.03"/>
<circle cx="68.2" cy="51.5" r="1.03"/>
<circle cx="78.9" cy="51.5" r="1.03"/>
<circle cx="91.2" cy="51.5" r="1.03"/>
<circle cx="102" cy="51.5" r="1.03"/>
<circle cx="114.3" cy="51.5" r="1.03"/>
<circle cx="125.1" cy="51.5" r="1.03"/>
<circle cx="137.4" cy="51.5" r="1.03"/>
<circle cx="148.1" cy="51.5" r="1.03"/>
<circle cx="160.4" cy="51.5" r="1.03"/>
<circle cx="171.2" cy="51.5" r="1.03"/>
<circle cx="183.5" cy="51.5" r="1.03"/>
<circle cx="194.2" cy="51.5" r="1.03"/>
<circle cx="206.5" cy="51.5" r="1.03"/>
<circle cx="217.3" cy="51.5" r="1.03"/>
<circle cx="229.6" cy="51.5" r="1.03"/>
<circle cx="240.3" cy="51.5" r="1.03"/>
<circle cx="252.6" cy="51.5" r="1.03"/>
<circle cx="260.1" cy="45.1" r="1.39"/>
<circle cx="266.3" cy="51.5" r="1.03"/>
<circle cx="278.6" cy="51.5" r="1.03"/>
<circle cx="15.5" cy="74.5" r="1.03"/>
<circle cx="27.8" cy="74.5" r="1.03"/>
<circle cx="38.6" cy="74.5" r="1.03"/>
<circle cx="50.9" cy="74.5" r="1.03"/>
<circle cx="64.5" cy="74.5" r="1.03"/>
<circle cx="76.8" cy="74.5" r="1.03"/>
<circle cx="90.5" cy="74.5" r="1.03"/>
<circle cx="102.8" cy="74.5" r="1.03"/>
<circle cx="113.5" cy="74.5" r="1.03"/>
<circle cx="125.8" cy="74.5" r="1.03"/>
<circle cx="136.6" cy="74.5" r="1.03"/>
<circle cx="148.9" cy="74.5" r="1.03"/>
<circle cx="159.6" cy="74.5" r="1.03"/>
<circle cx="171.9" cy="74.5" r="1.03"/>
<circle cx="182.7" cy="74.5" r="1.03"/>
<circle cx="195" cy="74.5" r="1.03"/>
<circle cx="205.8" cy="74.5" r="1.03"/>
<circle cx="218.1" cy="74.5" r="1.03"/>
<circle cx="228.8" cy="74.5" r="1.03"/>
<circle cx="241.1" cy="74.5" r="1.03"/>
<circle cx="250.7" cy="73" r="1.39"/>
<circle cx="260.5" cy="74.5" r="1.03"/>
<circle cx="272.8" cy="74.5" r="1.03"/>
<circle cx="15.5" cy="97.6" r="1.03"/>
<circle cx="27.8" cy="97.6" r="1.03"/>
<circle cx="33.8" cy="98.6" r="1.39"/>
<circle cx="38.6" cy="97.6" r="1.03"/>
<circle cx="50.9" cy="97.6" r="1.03"/>
<circle cx="61.6" cy="97.6" r="1.03"/>
<circle cx="73.9" cy="97.6" r="1.03"/>
<circle cx="108" cy="87.9" r="2.42"/>
<circle cx="116.4" cy="97.6" r="1.03"/>
<circle cx="128.7" cy="97.6" r="1.03"/>
<circle cx="137.1" cy="87.9" r="2.42"/>
<circle cx="165.7" cy="87.9" r="2.42"/>
<circle cx="174.1" cy="97.6" r="1.03"/>
<circle cx="186.4" cy="97.6" r="1.03"/>
<circle cx="194.7" cy="87.9" r="2.42"/>
<circle cx="214.4" cy="97.6" r="1.03"/>
<circle cx="226.7" cy="97.6" r="1.03"/>
<circle cx="240.3" cy="97.6" r="1.03"/>
<circle cx="252.6" cy="97.6" r="1.03"/>
<circle cx="260.4" cy="97.5" r="1.39"/>
<circle cx="266.3" cy="97.6" r="1.03"/>
<circle cx="278.6" cy="97.6" r="1.03"/>
<circle cx="9.7" cy="118.6" r=".3"/>
<circle cx="108" cy="106.1" r="1.82"/>
<circle cx="137.1" cy="106.1" r="1.82"/>
<circle cx="165.7" cy="106.1" r="1.82"/>
<circle cx="194.7" cy="106.1" r="1.82"/>
</g>
<use href="#words"/>
</svg>
